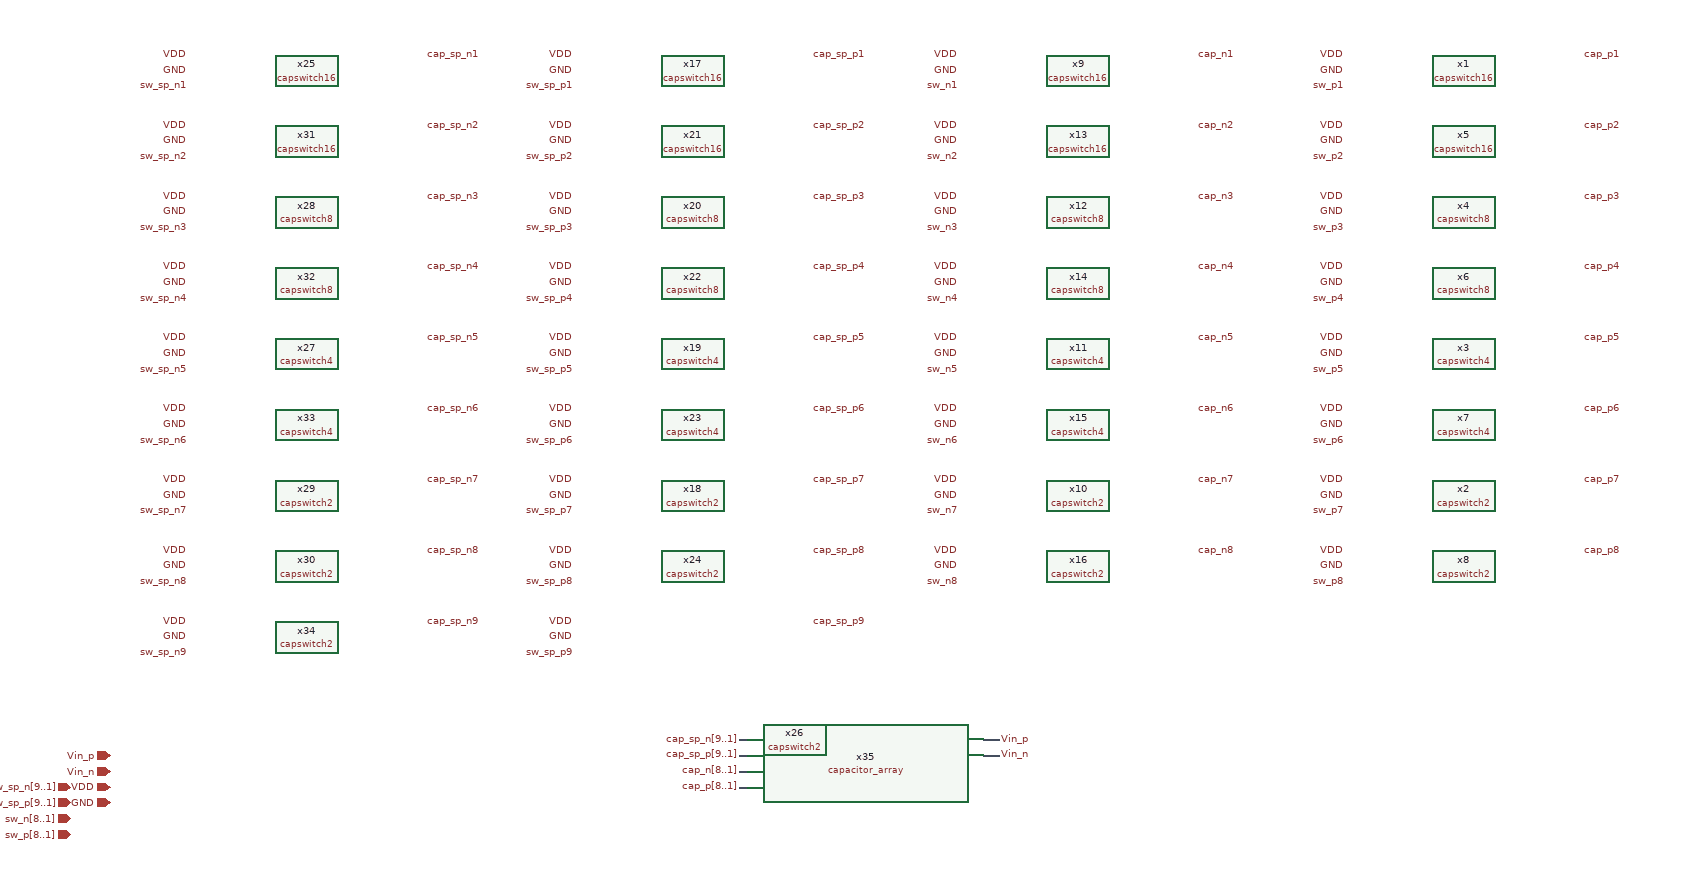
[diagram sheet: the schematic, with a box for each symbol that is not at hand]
v {xschem version=3.4.5 file_version=1.2
}
G {}
K {}
V {}
S {}
E {}
N 540 820 550 820 {
lab=cap_sp_n[9..1]}
N 540 840 550 840 {
lab=cap_sp_p[9..1]}
N 540 860 550 860 {
lab=cap_p[8..1]}
N 540 880 550 880 {
lab=cap_n[8..1]}
N 850 820 870 820 {
lab=Vin_p}
N 850 840 870 840 {
lab=Vin_n}
C {devices/lab_pin.sym} -160 -50 0 0 {name=p1 sig_type=std_logic lab=VDD}
C {devices/lab_pin.sym} -160 -30 0 0 {name=p2 sig_type=std_logic lab=GND
}
C {devices/lab_pin.sym} -160 40 0 0 {name=p3 sig_type=std_logic lab=VDD}
C {devices/lab_pin.sym} -160 60 0 0 {name=p4 sig_type=std_logic lab=GND
}
C {devices/lab_pin.sym} -160 130 0 0 {name=p5 sig_type=std_logic lab=VDD}
C {devices/lab_pin.sym} -160 150 0 0 {name=p6 sig_type=std_logic lab=GND
}
C {devices/lab_pin.sym} -160 220 0 0 {name=p7 sig_type=std_logic lab=VDD}
C {devices/lab_pin.sym} -160 240 0 0 {name=p8 sig_type=std_logic lab=GND
}
C {devices/lab_pin.sym} -160 310 0 0 {name=p9 sig_type=std_logic lab=VDD}
C {devices/lab_pin.sym} -160 330 0 0 {name=p10 sig_type=std_logic lab=GND
}
C {devices/lab_pin.sym} -160 400 0 0 {name=p11 sig_type=std_logic lab=VDD}
C {devices/lab_pin.sym} -160 420 0 0 {name=p12 sig_type=std_logic lab=GND
}
C {devices/lab_pin.sym} -160 490 0 0 {name=p13 sig_type=std_logic lab=VDD}
C {devices/lab_pin.sym} -160 510 0 0 {name=p15 sig_type=std_logic lab=GND
}
C {devices/lab_pin.sym} -160 580 0 0 {name=p16 sig_type=std_logic lab=VDD}
C {devices/lab_pin.sym} -160 600 0 0 {name=p19 sig_type=std_logic lab=GND
}
C {devices/lab_pin.sym} -160 670 0 0 {name=p20 sig_type=std_logic lab=VDD}
C {devices/lab_pin.sym} -160 690 0 0 {name=p21 sig_type=std_logic lab=GND
}
C {devices/lab_pin.sym} 330 670 0 0 {name=p23 sig_type=std_logic lab=VDD}
C {devices/lab_pin.sym} 330 690 0 0 {name=p24 sig_type=std_logic lab=GND
}
C {devices/lab_pin.sym} 330 580 0 0 {name=p25 sig_type=std_logic lab=VDD}
C {devices/lab_pin.sym} 330 600 0 0 {name=p26 sig_type=std_logic lab=GND
}
C {devices/lab_pin.sym} 330 490 0 0 {name=p27 sig_type=std_logic lab=VDD}
C {devices/lab_pin.sym} 330 510 0 0 {name=p28 sig_type=std_logic lab=GND
}
C {devices/lab_pin.sym} 330 400 0 0 {name=p29 sig_type=std_logic lab=VDD}
C {devices/lab_pin.sym} 330 420 0 0 {name=p30 sig_type=std_logic lab=GND
}
C {devices/lab_pin.sym} 330 310 0 0 {name=p31 sig_type=std_logic lab=VDD}
C {devices/lab_pin.sym} 330 330 0 0 {name=p32 sig_type=std_logic lab=GND
}
C {devices/lab_pin.sym} 330 220 0 0 {name=p33 sig_type=std_logic lab=VDD}
C {devices/lab_pin.sym} 330 240 0 0 {name=p34 sig_type=std_logic lab=GND
}
C {devices/lab_pin.sym} 330 130 0 0 {name=p35 sig_type=std_logic lab=VDD}
C {devices/lab_pin.sym} 330 150 0 0 {name=p36 sig_type=std_logic lab=GND
}
C {devices/lab_pin.sym} 330 40 0 0 {name=p37 sig_type=std_logic lab=VDD}
C {devices/lab_pin.sym} 330 60 0 0 {name=p38 sig_type=std_logic lab=GND
}
C {devices/lab_pin.sym} 330 -50 0 0 {name=p39 sig_type=std_logic lab=VDD}
C {devices/lab_pin.sym} 330 -30 0 0 {name=p40 sig_type=std_logic lab=GND
}
C {devices/lab_pin.sym} 820 -50 0 0 {name=p41 sig_type=std_logic lab=VDD}
C {devices/lab_pin.sym} 820 -30 0 0 {name=p42 sig_type=std_logic lab=GND
}
C {devices/lab_pin.sym} 820 40 0 0 {name=p43 sig_type=std_logic lab=VDD}
C {devices/lab_pin.sym} 820 60 0 0 {name=p44 sig_type=std_logic lab=GND
}
C {devices/lab_pin.sym} 820 130 0 0 {name=p45 sig_type=std_logic lab=VDD}
C {devices/lab_pin.sym} 820 150 0 0 {name=p46 sig_type=std_logic lab=GND
}
C {devices/lab_pin.sym} 820 220 0 0 {name=p47 sig_type=std_logic lab=VDD}
C {devices/lab_pin.sym} 820 240 0 0 {name=p48 sig_type=std_logic lab=GND
}
C {devices/lab_pin.sym} 820 310 0 0 {name=p49 sig_type=std_logic lab=VDD}
C {devices/lab_pin.sym} 820 330 0 0 {name=p50 sig_type=std_logic lab=GND
}
C {devices/lab_pin.sym} 820 400 0 0 {name=p51 sig_type=std_logic lab=VDD}
C {devices/lab_pin.sym} 820 420 0 0 {name=p52 sig_type=std_logic lab=GND
}
C {devices/lab_pin.sym} 820 490 0 0 {name=p53 sig_type=std_logic lab=VDD}
C {devices/lab_pin.sym} 820 510 0 0 {name=p54 sig_type=std_logic lab=GND
}
C {devices/lab_pin.sym} 820 580 0 0 {name=p55 sig_type=std_logic lab=VDD}
C {devices/lab_pin.sym} 820 600 0 0 {name=p56 sig_type=std_logic lab=GND
}
C {devices/lab_pin.sym} 1310 580 0 0 {name=p57 sig_type=std_logic lab=VDD}
C {devices/lab_pin.sym} 1310 600 0 0 {name=p58 sig_type=std_logic lab=GND
}
C {devices/lab_pin.sym} 1310 490 0 0 {name=p59 sig_type=std_logic lab=VDD}
C {devices/lab_pin.sym} 1310 510 0 0 {name=p60 sig_type=std_logic lab=GND
}
C {devices/lab_pin.sym} 1310 400 0 0 {name=p61 sig_type=std_logic lab=VDD}
C {devices/lab_pin.sym} 1310 420 0 0 {name=p62 sig_type=std_logic lab=GND
}
C {devices/lab_pin.sym} 1310 310 0 0 {name=p63 sig_type=std_logic lab=VDD}
C {devices/lab_pin.sym} 1310 330 0 0 {name=p64 sig_type=std_logic lab=GND
}
C {devices/lab_pin.sym} 1310 220 0 0 {name=p65 sig_type=std_logic lab=VDD}
C {devices/lab_pin.sym} 1310 240 0 0 {name=p66 sig_type=std_logic lab=GND
}
C {devices/lab_pin.sym} 1310 130 0 0 {name=p67 sig_type=std_logic lab=VDD}
C {devices/lab_pin.sym} 1310 150 0 0 {name=p68 sig_type=std_logic lab=GND
}
C {devices/lab_pin.sym} 1310 40 0 0 {name=p69 sig_type=std_logic lab=VDD}
C {devices/lab_pin.sym} 1310 60 0 0 {name=p70 sig_type=std_logic lab=GND
}
C {devices/lab_pin.sym} 1310 -50 0 0 {name=p71 sig_type=std_logic lab=VDD}
C {devices/lab_pin.sym} 1310 -30 0 0 {name=p72 sig_type=std_logic lab=GND
}
C {devices/lab_pin.sym} -160 -10 0 0 {name=p73 sig_type=std_logic lab=sw_sp_n1}
C {devices/lab_pin.sym} -160 80 0 0 {name=p74 sig_type=std_logic lab=sw_sp_n2}
C {devices/lab_pin.sym} -160 170 0 0 {name=p75 sig_type=std_logic lab=sw_sp_n3}
C {devices/lab_pin.sym} -160 260 0 0 {name=p76 sig_type=std_logic lab=sw_sp_n4}
C {devices/lab_pin.sym} -160 350 0 0 {name=p77 sig_type=std_logic lab=sw_sp_n5}
C {devices/lab_pin.sym} -160 440 0 0 {name=p78 sig_type=std_logic lab=sw_sp_n6}
C {devices/lab_pin.sym} -160 530 0 0 {name=p79 sig_type=std_logic lab=sw_sp_n7}
C {devices/lab_pin.sym} -160 620 0 0 {name=p80 sig_type=std_logic lab=sw_sp_n8}
C {devices/lab_pin.sym} -160 710 0 0 {name=p81 sig_type=std_logic lab=sw_sp_n9}
C {devices/lab_pin.sym} 330 -10 0 0 {name=l47 sig_type=std_logic lab=sw_sp_p1
}
C {devices/lab_pin.sym} 330 80 0 0 {name=l1 sig_type=std_logic lab=sw_sp_p2
}
C {devices/lab_pin.sym} 330 170 0 0 {name=l2 sig_type=std_logic lab=sw_sp_p3
}
C {devices/lab_pin.sym} 330 260 0 0 {name=l3 sig_type=std_logic lab=sw_sp_p4
}
C {devices/lab_pin.sym} 330 350 0 0 {name=l4 sig_type=std_logic lab=sw_sp_p5
}
C {devices/lab_pin.sym} 330 440 0 0 {name=l5 sig_type=std_logic lab=sw_sp_p6
}
C {devices/lab_pin.sym} 330 530 0 0 {name=l6 sig_type=std_logic lab=sw_sp_p7
}
C {devices/lab_pin.sym} 330 620 0 0 {name=l7 sig_type=std_logic lab=sw_sp_p8
}
C {devices/lab_pin.sym} 330 710 0 0 {name=l8 sig_type=std_logic lab=sw_sp_p9
}
C {devices/lab_pin.sym} 820 -10 0 0 {name=l115 sig_type=std_logic lab=sw_n1
}
C {devices/lab_pin.sym} 820 80 0 0 {name=l9 sig_type=std_logic lab=sw_n2
}
C {devices/lab_pin.sym} 820 170 0 0 {name=l10 sig_type=std_logic lab=sw_n3
}
C {devices/lab_pin.sym} 820 260 0 0 {name=l11 sig_type=std_logic lab=sw_n4
}
C {devices/lab_pin.sym} 820 350 0 0 {name=l12 sig_type=std_logic lab=sw_n5
}
C {devices/lab_pin.sym} 820 440 0 0 {name=l13 sig_type=std_logic lab=sw_n6
}
C {devices/lab_pin.sym} 820 530 0 0 {name=l14 sig_type=std_logic lab=sw_n7
}
C {devices/lab_pin.sym} 820 620 0 0 {name=l15 sig_type=std_logic lab=sw_n8
}
C {devices/lab_pin.sym} 1310 -10 0 0 {name=l83 sig_type=std_logic lab=sw_p1
}
C {devices/lab_pin.sym} 1310 80 0 0 {name=l16 sig_type=std_logic lab=sw_p2
}
C {devices/lab_pin.sym} 1310 170 0 0 {name=l17 sig_type=std_logic lab=sw_p3
}
C {devices/lab_pin.sym} 1310 260 0 0 {name=l18 sig_type=std_logic lab=sw_p4
}
C {devices/lab_pin.sym} 1310 350 0 0 {name=l19 sig_type=std_logic lab=sw_p5
}
C {devices/lab_pin.sym} 1310 440 0 0 {name=l20 sig_type=std_logic lab=sw_p6
}
C {devices/lab_pin.sym} 1310 530 0 0 {name=l21 sig_type=std_logic lab=sw_p7
}
C {devices/lab_pin.sym} 1310 620 0 0 {name=l22 sig_type=std_logic lab=sw_p8
}
C {devices/lab_pin.sym} 140 -50 2 0 {name=l23 sig_type=std_logic lab=cap_sp_n1
}
C {devices/lab_pin.sym} 630 -50 2 0 {name=l44 sig_type=std_logic lab=cap_sp_p1
}
C {devices/lab_pin.sym} 1120 -50 2 0 {name=l112 sig_type=std_logic lab=cap_n1
}
C {devices/lab_pin.sym} 1610 -50 2 0 {name=l80 sig_type=std_logic lab=cap_p1
}
C {devices/lab_pin.sym} 140 40 2 0 {name=l24 sig_type=std_logic lab=cap_sp_n2
}
C {devices/lab_pin.sym} 140 130 2 0 {name=l25 sig_type=std_logic lab=cap_sp_n3
}
C {devices/lab_pin.sym} 140 220 2 0 {name=l26 sig_type=std_logic lab=cap_sp_n4
}
C {devices/lab_pin.sym} 140 310 2 0 {name=l27 sig_type=std_logic lab=cap_sp_n5
}
C {devices/lab_pin.sym} 140 400 2 0 {name=l28 sig_type=std_logic lab=cap_sp_n6
}
C {devices/lab_pin.sym} 140 490 2 0 {name=l29 sig_type=std_logic lab=cap_sp_n7
}
C {devices/lab_pin.sym} 140 580 2 0 {name=l30 sig_type=std_logic lab=cap_sp_n8
}
C {devices/lab_pin.sym} 140 670 2 0 {name=l31 sig_type=std_logic lab=cap_sp_n9
}
C {devices/lab_pin.sym} 630 40 2 0 {name=l32 sig_type=std_logic lab=cap_sp_p2
}
C {devices/lab_pin.sym} 630 130 2 0 {name=l33 sig_type=std_logic lab=cap_sp_p3
}
C {devices/lab_pin.sym} 630 220 2 0 {name=l34 sig_type=std_logic lab=cap_sp_p4
}
C {devices/lab_pin.sym} 630 310 2 0 {name=l35 sig_type=std_logic lab=cap_sp_p5
}
C {devices/lab_pin.sym} 630 400 2 0 {name=l36 sig_type=std_logic lab=cap_sp_p6
}
C {devices/lab_pin.sym} 630 490 2 0 {name=l37 sig_type=std_logic lab=cap_sp_p7
}
C {devices/lab_pin.sym} 630 580 2 0 {name=l38 sig_type=std_logic lab=cap_sp_p8
}
C {devices/lab_pin.sym} 630 670 2 0 {name=l39 sig_type=std_logic lab=cap_sp_p9
}
C {devices/lab_pin.sym} 1120 40 2 0 {name=l40 sig_type=std_logic lab=cap_n2
}
C {devices/lab_pin.sym} 1120 130 2 0 {name=l41 sig_type=std_logic lab=cap_n3
}
C {devices/lab_pin.sym} 1120 220 2 0 {name=l42 sig_type=std_logic lab=cap_n4
}
C {devices/lab_pin.sym} 1120 310 2 0 {name=l43 sig_type=std_logic lab=cap_n5
}
C {devices/lab_pin.sym} 1120 400 2 0 {name=l45 sig_type=std_logic lab=cap_n6
}
C {devices/lab_pin.sym} 1120 490 2 0 {name=l46 sig_type=std_logic lab=cap_n7
}
C {devices/lab_pin.sym} 1120 580 2 0 {name=l48 sig_type=std_logic lab=cap_n8
}
C {devices/lab_pin.sym} 1610 40 2 0 {name=l49 sig_type=std_logic lab=cap_p2
}
C {devices/lab_pin.sym} 1610 130 2 0 {name=l50 sig_type=std_logic lab=cap_p3
}
C {devices/lab_pin.sym} 1610 220 2 0 {name=l51 sig_type=std_logic lab=cap_p4
}
C {devices/lab_pin.sym} 1610 310 2 0 {name=l52 sig_type=std_logic lab=cap_p5
}
C {devices/lab_pin.sym} 1610 400 2 0 {name=l53 sig_type=std_logic lab=cap_p6
}
C {devices/lab_pin.sym} 1610 490 2 0 {name=l54 sig_type=std_logic lab=cap_p7
}
C {devices/lab_pin.sym} 1610 580 2 0 {name=l55 sig_type=std_logic lab=cap_p8}
C {devices/lab_pin.sym} 540 820 0 0 {name=l56 sig_type=std_logic lab=cap_sp_n[9..1]
}
C {devices/lab_pin.sym} 540 840 0 0 {name=l57 sig_type=std_logic lab=cap_sp_p[9..1]
}
C {devices/lab_pin.sym} 540 880 0 0 {name=l58 sig_type=std_logic lab=cap_p[8..1]
}
C {devices/lab_pin.sym} 540 860 0 0 {name=l59 sig_type=std_logic lab=cap_n[8..1]
}
C {devices/lab_pin.sym} 870 820 2 0 {name=l60 sig_type=std_logic lab=Vin_p
}
C {devices/lab_pin.sym} 870 840 2 0 {name=l61 sig_type=std_logic lab=Vin_n
}
C {devices/ipin.sym} -310 880 0 0 {name=p14 lab=sw_sp_n[9..1]
}
C {devices/ipin.sym} -310 900 0 0 {name=p22 lab=sw_sp_p[9..1]
}
C {devices/ipin.sym} -310 920 0 0 {name=p82 lab=sw_n[8..1]
}
C {devices/ipin.sym} -310 940 0 0 {name=p83 lab=sw_p[8..1]
}
C {devices/iopin.sym} -260 840 0 0 {name=p84 lab=Vin_p
}
C {devices/iopin.sym} -260 860 0 0 {name=p85 lab=Vin_n
}
C {devices/iopin.sym} -260 880 0 0 {name=p17 lab=VDD
}
C {devices/iopin.sym} -260 900 0 0 {name=p18 lab=GND
}
C {caparray/capacitor_array.sym} 700 850 0 0 {name=x35}
C {capswitch16/capswitch16.sym} 1460 -30 0 0 {name=x1}
C {capswitch16/capswitch16.sym} 1460 60 0 0 {name=x5}
C {capswitch16/capswitch16.sym} 970 -30 0 0 {name=x9}
C {capswitch16/capswitch16.sym} 970 60 0 0 {name=x13}
C {capswitch16/capswitch16.sym} 480 -30 0 0 {name=x17}
C {capswitch16/capswitch16.sym} 480 60 0 0 {name=x21}
C {capswitch16/capswitch16.sym} -10 -30 0 0 {name=x25}
C {capswitch16/capswitch16.sym} -10 60 0 0 {name=x31}
C {capswitch8/capswitch8.sym} 1460 150 0 0 {name=x4}
C {capswitch8/capswitch8.sym} 1460 240 0 0 {name=x6}
C {capswitch8/capswitch8.sym} 970 150 0 0 {name=x12}
C {capswitch8/capswitch8.sym} 970 240 0 0 {name=x14}
C {capswitch8/capswitch8.sym} 480 150 0 0 {name=x20}
C {capswitch8/capswitch8.sym} 480 240 0 0 {name=x22}
C {capswitch8/capswitch8.sym} -10 150 0 0 {name=x28}
C {capswitch8/capswitch8.sym} -10 240 0 0 {name=x32}
C {capswitch4/capswitch4.sym} 1460 330 0 0 {name=x3}
C {capswitch4/capswitch4.sym} 1460 420 0 0 {name=x7}
C {capswitch4/capswitch4.sym} 970 330 0 0 {name=x11}
C {capswitch4/capswitch4.sym} 970 420 0 0 {name=x15}
C {capswitch4/capswitch4.sym} 480 330 0 0 {name=x19}
C {capswitch4/capswitch4.sym} 480 420 0 0 {name=x23}
C {capswitch4/capswitch4.sym} -10 330 0 0 {name=x27}
C {capswitch4/capswitch4.sym} -10 420 0 0 {name=x33}
C {capswitch2/capswitch2.sym} 1460 510 0 0 {name=x2}
C {capswitch2/capswitch2.sym} 1460 600 0 0 {name=x8}
C {capswitch2/capswitch2.sym} 970 510 0 0 {name=x10}
C {capswitch2/capswitch2.sym} 970 600 0 0 {name=x16}
C {capswitch2/capswitch2.sym} 480 510 0 0 {name=x18}
C {capswitch2/capswitch2.sym} 480 600 0 0 {name=x24}
C {capswitch2/capswitch2.sym} 480 690 0 0 {name=x26}
C {capswitch2/capswitch2.sym} -10 510 0 0 {name=x29}
C {capswitch2/capswitch2.sym} -10 600 0 0 {name=x30}
C {capswitch2/capswitch2.sym} -10 690 0 0 {name=x34}
